VERSION 5.7 ;
  NOWIREEXTENSIONATPIN ON ;
  DIVIDERCHAR "/" ;
  BUSBITCHARS "[]" ;
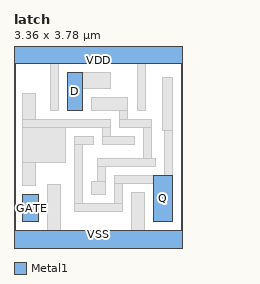
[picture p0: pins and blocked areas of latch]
MACRO latch
  CLASS CORE ;
  FOREIGN latch ;
  ORIGIN 0.000 0.000 ;
  SIZE 3.360 BY 3.780 ;
  SITE CoreSite ;
  SYMMETRY X Y ;
  PIN Q
    DIRECTION OUTPUT ;
    ANTENNAGATEAREA 0.180700 ;
    ANTENNADIFFAREA 0.720800 ;
    PORT
      LAYER Metal1 ;
        RECT 2.780 0.400 3.160 1.320 ;
    END
  END Q
  PIN D
    DIRECTION INPUT ;
    ANTENNAGATEAREA 0.180700 ;
    PORT
      LAYER Metal1 ;
        RECT 1.060 2.620 1.360 3.380 ;
    END
  END D
  PIN VSS
    DIRECTION INOUT ;
    USE GROUND ;
    PORT
      LAYER Metal1 ;
        RECT 0.000 -0.220 3.360 0.220 ;
    END
  END VSS
  PIN VDD
    DIRECTION INOUT ;
    USE POWER ;
    PORT
      LAYER Metal1 ;
        RECT 0.000 3.560 3.360 4.000 ;
    END
  END VDD
  PIN GATE
    DIRECTION INPUT ;
    ANTENNAGATEAREA 0.361400 ;
    PORT
      LAYER Metal1 ;
        RECT 0.160 0.400 0.490 0.950 ;
    END
  END GATE
  OBS
      LAYER Metal1 ;
        RECT 0.160 2.440 0.420 2.955 ;
        RECT 0.720 2.620 0.880 3.560 ;
        RECT 1.360 3.060 1.915 3.380 ;
        RECT 1.540 2.620 2.260 2.880 ;
        RECT 2.450 2.620 2.610 3.560 ;
        RECT 2.100 2.440 2.260 2.620 ;
        RECT 0.160 2.280 1.920 2.440 ;
        RECT 2.100 2.280 2.740 2.440 ;
        RECT 0.160 1.580 1.020 2.280 ;
        RECT 1.760 2.100 1.920 2.280 ;
        RECT 1.200 1.940 1.580 2.100 ;
        RECT 1.760 1.940 2.400 2.100 ;
        RECT 0.160 1.130 0.420 1.580 ;
        RECT 0.670 0.220 0.930 1.150 ;
        RECT 1.200 0.760 1.360 1.940 ;
        RECT 2.580 1.660 2.740 2.280 ;
        RECT 2.960 2.220 3.160 3.280 ;
        RECT 1.660 1.500 2.820 1.660 ;
        RECT 1.660 1.200 1.820 1.500 ;
        RECT 3.000 1.320 3.160 2.220 ;
        RECT 1.540 0.940 1.820 1.200 ;
        RECT 2.000 1.160 2.780 1.320 ;
        RECT 2.000 0.760 2.160 1.160 ;
        RECT 1.200 0.600 2.160 0.760 ;
        RECT 2.340 0.220 2.600 0.980 ;
  END
END latch
END LIBRARY

